VERSION 5.7 ;
  NOWIREEXTENSIONATPIN ON ;
  DIVIDERCHAR "/" ;
  BUSBITCHARS "[]" ;
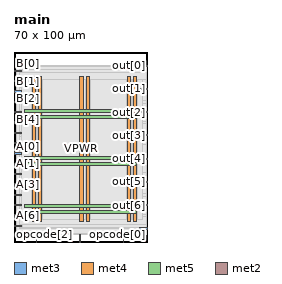
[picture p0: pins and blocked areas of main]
MACRO main
  CLASS BLOCK ;
  FOREIGN main ;
  ORIGIN 0.000 0.000 ;
  SIZE 70.000 BY 100.000 ;
  PIN A[0]
    DIRECTION INPUT ;
    USE SIGNAL ;
    ANTENNAGATEAREA 0.196500 ;
    PORT
      LAYER met3 ;
        RECT 0.000 46.280 4.000 46.880 ;
    END
  END A[0]
  PIN A[1]
    DIRECTION INPUT ;
    USE SIGNAL ;
    ANTENNAGATEAREA 0.213000 ;
    PORT
      LAYER met3 ;
        RECT 0.000 40.840 4.000 41.440 ;
    END
  END A[1]
  PIN A[2]
    DIRECTION INPUT ;
    USE SIGNAL ;
    ANTENNAGATEAREA 0.213000 ;
    PORT
      LAYER met3 ;
        RECT 0.000 35.400 4.000 36.000 ;
    END
  END A[2]
  PIN A[3]
    DIRECTION INPUT ;
    USE SIGNAL ;
    ANTENNAGATEAREA 0.213000 ;
    PORT
      LAYER met3 ;
        RECT 0.000 29.960 4.000 30.560 ;
    END
  END A[3]
  PIN A[4]
    DIRECTION INPUT ;
    USE SIGNAL ;
    ANTENNAGATEAREA 0.159000 ;
    PORT
      LAYER met3 ;
        RECT 0.000 24.520 4.000 25.120 ;
    END
  END A[4]
  PIN A[5]
    DIRECTION INPUT ;
    USE SIGNAL ;
    ANTENNAGATEAREA 0.213000 ;
    PORT
      LAYER met3 ;
        RECT 0.000 19.080 4.000 19.680 ;
    END
  END A[5]
  PIN A[6]
    DIRECTION INPUT ;
    USE SIGNAL ;
    ANTENNAGATEAREA 0.159000 ;
    PORT
      LAYER met3 ;
        RECT 0.000 13.640 4.000 14.240 ;
    END
  END A[6]
  PIN A[7]
    DIRECTION INPUT ;
    USE SIGNAL ;
    ANTENNAGATEAREA 0.213000 ;
    PORT
      LAYER met3 ;
        RECT 0.000 8.200 4.000 8.800 ;
    END
  END A[7]
  PIN B[0]
    DIRECTION INPUT ;
    USE SIGNAL ;
    ANTENNAGATEAREA 0.213000 ;
    PORT
      LAYER met3 ;
        RECT 0.000 89.800 4.000 90.400 ;
    END
  END B[0]
  PIN B[1]
    DIRECTION INPUT ;
    USE SIGNAL ;
    ANTENNAGATEAREA 0.196500 ;
    PORT
      LAYER met3 ;
        RECT 0.000 84.360 4.000 84.960 ;
    END
  END B[1]
  PIN B[2]
    DIRECTION INPUT ;
    USE SIGNAL ;
    ANTENNAGATEAREA 0.213000 ;
    PORT
      LAYER met3 ;
        RECT 0.000 78.920 4.000 79.520 ;
    END
  END B[2]
  PIN B[3]
    DIRECTION INPUT ;
    USE SIGNAL ;
    ANTENNAGATEAREA 0.126000 ;
    PORT
      LAYER met3 ;
        RECT 0.000 73.480 4.000 74.080 ;
    END
  END B[3]
  PIN B[4]
    DIRECTION INPUT ;
    USE SIGNAL ;
    ANTENNAGATEAREA 0.159000 ;
    PORT
      LAYER met3 ;
        RECT 0.000 68.040 4.000 68.640 ;
    END
  END B[4]
  PIN B[5]
    DIRECTION INPUT ;
    USE SIGNAL ;
    ANTENNAGATEAREA 0.213000 ;
    PORT
      LAYER met3 ;
        RECT 0.000 62.600 4.000 63.200 ;
    END
  END B[5]
  PIN B[6]
    DIRECTION INPUT ;
    USE SIGNAL ;
    ANTENNAGATEAREA 0.159000 ;
    PORT
      LAYER met3 ;
        RECT 0.000 57.160 4.000 57.760 ;
    END
  END B[6]
  PIN B[7]
    DIRECTION INPUT ;
    USE SIGNAL ;
    ANTENNAGATEAREA 0.126000 ;
    PORT
      LAYER met3 ;
        RECT 0.000 51.720 4.000 52.320 ;
    END
  END B[7]
  PIN VGND
    DIRECTION INOUT ;
    USE GROUND ;
    PORT
      LAYER met4 ;
        RECT 13.020 10.640 14.620 87.280 ;
    END
    PORT
      LAYER met4 ;
        RECT 38.020 10.640 39.620 87.280 ;
    END
    PORT
      LAYER met4 ;
        RECT 63.020 10.640 64.620 87.280 ;
    END
    PORT
      LAYER met5 ;
        RECT 5.280 18.380 64.640 19.980 ;
    END
    PORT
      LAYER met5 ;
        RECT 5.280 43.380 64.640 44.980 ;
    END
    PORT
      LAYER met5 ;
        RECT 5.280 68.380 64.640 69.980 ;
    END
  END VGND
  PIN VPWR
    DIRECTION INOUT ;
    USE POWER ;
    PORT
      LAYER met4 ;
        RECT 9.720 10.640 11.320 87.280 ;
    END
    PORT
      LAYER met4 ;
        RECT 34.720 10.640 36.320 87.280 ;
    END
    PORT
      LAYER met4 ;
        RECT 59.720 10.640 61.320 87.280 ;
    END
    PORT
      LAYER met5 ;
        RECT 5.280 15.080 64.640 16.680 ;
    END
    PORT
      LAYER met5 ;
        RECT 5.280 40.080 64.640 41.680 ;
    END
    PORT
      LAYER met5 ;
        RECT 5.280 65.080 64.640 66.680 ;
    END
  END VPWR
  PIN opcode[0]
    DIRECTION INPUT ;
    USE SIGNAL ;
    ANTENNAGATEAREA 0.213000 ;
    PORT
      LAYER met2 ;
        RECT 57.590 0.000 57.870 4.000 ;
    END
  END opcode[0]
  PIN opcode[1]
    DIRECTION INPUT ;
    USE SIGNAL ;
    ANTENNAGATEAREA 0.159000 ;
    PORT
      LAYER met2 ;
        RECT 34.590 0.000 34.870 4.000 ;
    END
  END opcode[1]
  PIN opcode[2]
    DIRECTION INPUT ;
    USE SIGNAL ;
    ANTENNAGATEAREA 0.213000 ;
    PORT
      LAYER met2 ;
        RECT 11.590 0.000 11.870 4.000 ;
    END
  END opcode[2]
  PIN out[0]
    DIRECTION OUTPUT ;
    USE SIGNAL ;
    ANTENNADIFFAREA 0.445500 ;
    PORT
      LAYER met3 ;
        RECT 66.000 92.520 70.000 93.120 ;
    END
  END out[0]
  PIN out[1]
    DIRECTION OUTPUT ;
    USE SIGNAL ;
    ANTENNADIFFAREA 0.445500 ;
    PORT
      LAYER met3 ;
        RECT 66.000 80.280 70.000 80.880 ;
    END
  END out[1]
  PIN out[2]
    DIRECTION OUTPUT ;
    USE SIGNAL ;
    ANTENNADIFFAREA 0.445500 ;
    PORT
      LAYER met3 ;
        RECT 66.000 68.040 70.000 68.640 ;
    END
  END out[2]
  PIN out[3]
    DIRECTION OUTPUT ;
    USE SIGNAL ;
    ANTENNADIFFAREA 0.445500 ;
    PORT
      LAYER met3 ;
        RECT 66.000 55.800 70.000 56.400 ;
    END
  END out[3]
  PIN out[4]
    DIRECTION OUTPUT ;
    USE SIGNAL ;
    ANTENNADIFFAREA 0.445500 ;
    PORT
      LAYER met3 ;
        RECT 66.000 43.560 70.000 44.160 ;
    END
  END out[4]
  PIN out[5]
    DIRECTION OUTPUT ;
    USE SIGNAL ;
    ANTENNADIFFAREA 0.891000 ;
    PORT
      LAYER met3 ;
        RECT 66.000 31.320 70.000 31.920 ;
    END
  END out[5]
  PIN out[6]
    DIRECTION OUTPUT ;
    USE SIGNAL ;
    ANTENNADIFFAREA 0.445500 ;
    PORT
      LAYER met3 ;
        RECT 66.000 19.080 70.000 19.680 ;
    END
  END out[6]
  PIN out[7]
    DIRECTION OUTPUT ;
    USE SIGNAL ;
    ANTENNADIFFAREA 0.445500 ;
    PORT
      LAYER met3 ;
        RECT 66.000 6.840 70.000 7.440 ;
    END
  END out[7]
  OBS
      LAYER nwell ;
        RECT 5.330 10.795 64.590 87.125 ;
      LAYER li1 ;
        RECT 5.520 10.795 64.400 87.125 ;
      LAYER met1 ;
        RECT 1.450 10.640 69.850 87.680 ;
      LAYER met2 ;
        RECT 1.480 4.280 69.830 93.005 ;
        RECT 1.480 4.000 11.310 4.280 ;
        RECT 12.150 4.000 34.310 4.280 ;
        RECT 35.150 4.000 57.310 4.280 ;
        RECT 58.150 4.000 69.830 4.280 ;
      LAYER met3 ;
        RECT 2.825 92.120 65.600 92.985 ;
        RECT 2.825 90.800 69.855 92.120 ;
        RECT 4.400 89.400 69.855 90.800 ;
        RECT 2.825 85.360 69.855 89.400 ;
        RECT 4.400 83.960 69.855 85.360 ;
        RECT 2.825 81.280 69.855 83.960 ;
        RECT 2.825 79.920 65.600 81.280 ;
        RECT 4.400 79.880 65.600 79.920 ;
        RECT 4.400 78.520 69.855 79.880 ;
        RECT 2.825 74.480 69.855 78.520 ;
        RECT 4.400 73.080 69.855 74.480 ;
        RECT 2.825 69.040 69.855 73.080 ;
        RECT 4.400 67.640 65.600 69.040 ;
        RECT 2.825 63.600 69.855 67.640 ;
        RECT 4.400 62.200 69.855 63.600 ;
        RECT 2.825 58.160 69.855 62.200 ;
        RECT 4.400 56.800 69.855 58.160 ;
        RECT 4.400 56.760 65.600 56.800 ;
        RECT 2.825 55.400 65.600 56.760 ;
        RECT 2.825 52.720 69.855 55.400 ;
        RECT 4.400 51.320 69.855 52.720 ;
        RECT 2.825 47.280 69.855 51.320 ;
        RECT 4.400 45.880 69.855 47.280 ;
        RECT 2.825 44.560 69.855 45.880 ;
        RECT 2.825 43.160 65.600 44.560 ;
        RECT 2.825 41.840 69.855 43.160 ;
        RECT 4.400 40.440 69.855 41.840 ;
        RECT 2.825 36.400 69.855 40.440 ;
        RECT 4.400 35.000 69.855 36.400 ;
        RECT 2.825 32.320 69.855 35.000 ;
        RECT 2.825 30.960 65.600 32.320 ;
        RECT 4.400 30.920 65.600 30.960 ;
        RECT 4.400 29.560 69.855 30.920 ;
        RECT 2.825 25.520 69.855 29.560 ;
        RECT 4.400 24.120 69.855 25.520 ;
        RECT 2.825 20.080 69.855 24.120 ;
        RECT 4.400 18.680 65.600 20.080 ;
        RECT 2.825 14.640 69.855 18.680 ;
        RECT 4.400 13.240 69.855 14.640 ;
        RECT 2.825 9.200 69.855 13.240 ;
        RECT 4.400 7.840 69.855 9.200 ;
        RECT 4.400 7.800 65.600 7.840 ;
        RECT 2.825 6.975 65.600 7.800 ;
      LAYER met4 ;
        RECT 3.975 11.735 9.320 85.505 ;
        RECT 11.720 11.735 12.620 85.505 ;
        RECT 15.020 11.735 34.320 85.505 ;
        RECT 36.720 11.735 37.620 85.505 ;
        RECT 40.020 11.735 59.320 85.505 ;
        RECT 61.720 11.735 62.620 85.505 ;
        RECT 65.020 11.735 67.785 85.505 ;
  END
END main
END LIBRARY

